VERSION 5.8 ;
BUSBITCHARS "[]" ;
DIVIDERCHAR "/" ;

UNITS
  DATABASE MICRONS 1000 ;
END UNITS

MANUFACTURINGGRID 0.005 ;

SITE core
  CLASS CORE ;
  SYMMETRY Y ;
  SIZE 2.0 BY 30.0 ;
END core

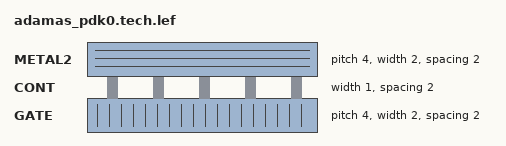
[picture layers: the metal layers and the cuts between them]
LAYER GATE
  TYPE ROUTING ;
  DIRECTION VERTICAL ;
  PITCH 4.0 ;
  OFFSET 2.0 ;
  WIDTH 2 ;
  SPACING 2 ;
  RESISTANCE RPERSQ 0.1 ;
  CAPACITANCE CPERSQDIST 5e-05 ;
END GATE

LAYER CONT
  TYPE CUT ;
  SPACING 2 ;
  WIDTH 1 ;
  RESISTANCE 1 ;
END CONT

LAYER METAL2
  TYPE ROUTING ;
  DIRECTION HORIZONTAL ;
  PITCH 4.0 ;
  OFFSET 2.0 ;
  WIDTH 2 ;
  SPACING 2 ;
  RESISTANCE RPERSQ 0.05 ;
  CAPACITANCE CPERSQDIST 5e-05 ;
END METAL2

VIA CONT_GATE_METAL2 DEFAULT
  LAYER GATE ;
    RECT -1 -1 1 1 ;
  LAYER CONT ;
    RECT -0.5 -0.5 0.5 0.5 ;
  LAYER METAL2 ;
    RECT -1 -1 1 1 ;
END CONT_GATE_METAL2

END LIBRARY
